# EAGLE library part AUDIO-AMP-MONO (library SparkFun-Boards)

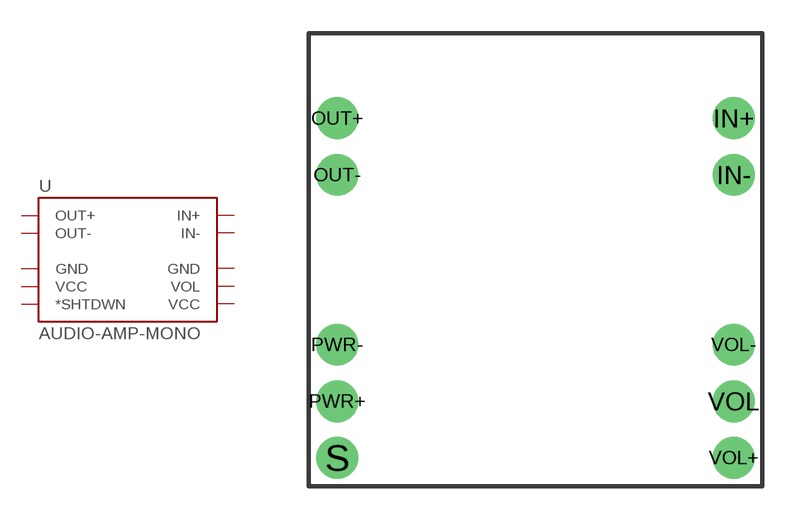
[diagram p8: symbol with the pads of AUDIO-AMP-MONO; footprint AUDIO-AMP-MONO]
Designator prefix U

## AUDIO-AMP-MONODIP  [AUDIO-AMP-MONO]
IN+  IN+
IN-  IN-
OUT+  OUT+
OUT-  OUT-
PWR+  VCC
PWR-  GND
S  *SHTDWN
VOL  VOL
VOL+  VCC
VOL-  GND

## Footprint AUDIO-AMP-MONO (pad centres in mm)
drill 1.016 pad 1.88: IN+ 8.89,6.35; IN- 8.89,3.81; OUT+ -8.89,6.35; OUT- -8.89,3.81; PWR+ -8.89,-6.35; PWR- -8.89,-3.81; S -8.89,-8.89; VOL 8.89,-6.35; VOL+ 8.89,-8.89; VOL- 8.89,-3.81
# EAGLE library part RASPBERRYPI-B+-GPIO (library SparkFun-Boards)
Raspberry Pi B+ GPIO Header 2x20 pin connector

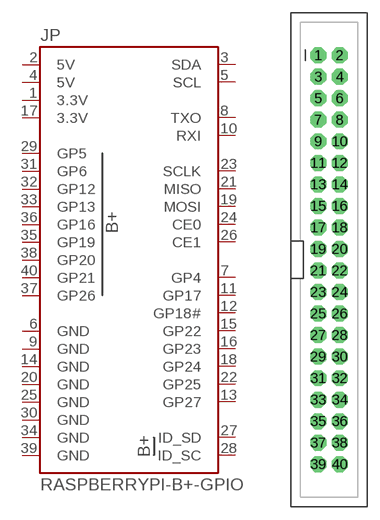
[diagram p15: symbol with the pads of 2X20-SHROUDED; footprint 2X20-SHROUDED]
Designator prefix JP

## RASPBERRYPI-B+-GPIO  [2X20-SHROUDED]
1  3.3V  pwr
2  5V  pwr
3  SDA
4  5V  pwr
5  SCL
6  GND  pwr
7  GP4
8  TXO  out
9  GND  pwr
10  RXI  in
11  GP17
12  GP18#
13  GP27
14  GND  pwr
15  GP22
16  GP23
17  3.3V  pwr
18  GP24
19  MOSI  out
20  GND  pwr
21  MISO  in
22  GP25
23  SCLK  out
24  CE0  out
25  GND  pwr
26  CE1  out
27  ID_SD
28  ID_SC
29  GP5
30  GND  pwr
31  GP6
32  GP12
33  GP13
34  GND  pwr
35  GP19
36  GP16
37  GP26
38  GP20
39  GND  pwr
40  GP21

## Footprint 2X20-SHROUDED (pad centres in mm)
drill 1.016 pad 1.88 octagon: 1 -1.27,24.13; 2 1.27,24.13; 3 -1.27,21.59; 4 1.27,21.59; 5 -1.27,19.05; 6 1.27,19.05; 7 -1.27,16.51; 8 1.27,16.51; 9 -1.27,13.97; 10 1.27,13.97; 11 -1.27,11.43; 12 1.27,11.43; 13 -1.27,8.89; 14 1.27,8.89; 15 -1.27,6.35; 16 1.27,6.35; 17 -1.27,3.81; 18 1.27,3.81; 19 -1.27,1.27; 20 1.27,1.27; 21 -1.27,-1.27; 22 1.27,-1.27; 23 -1.27,-3.81; 24 1.27,-3.81; 25 -1.27,-6.35; 26 1.27,-6.35; 27 -1.27,-8.89; 28 1.27,-8.89; 29 -1.27,-11.43; 30 1.27,-11.43; 31 -1.27,-13.97; 32 1.27,-13.97; 33 -1.27,-16.51; 34 1.27,-16.51; 35 -1.27,-19.05; 36 1.27,-19.05; 37 -1.27,-21.59; 38 1.27,-21.59; 39 -1.27,-24.13; 40 1.27,-24.13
